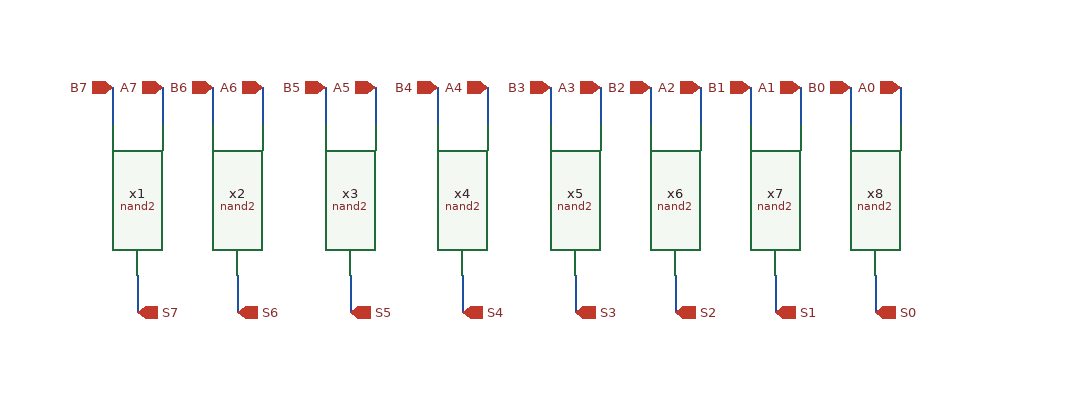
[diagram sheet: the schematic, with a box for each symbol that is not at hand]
v {xschem version=3.1.0 file_version=1.2 }
G {}
K {}
V {}
S {}
E {}
N 2260 -940 2260 -910 {
lab=A7}
N 2430 -940 2430 -910 {
lab=A5}
N 2340 -940 2340 -910 {
lab=A6}
N 2520 -940 2520 -910 {
lab=A4}
N 2610 -940 2610 -910 {
lab=A3}
N 2690 -940 2690 -910 {
lab=A2}
N 2770 -940 2770 -910 {
lab=A1}
N 2850 -940 2850 -910 {
lab=A0}
N 2220 -940 2220 -910 {
lab=B7}
N 2390 -940 2390 -910 {
lab=B5}
N 2300 -940 2300 -910 {
lab=B6}
N 2480 -940 2480 -910 {
lab=B4}
N 2570 -940 2570 -910 {
lab=B3}
N 2650 -940 2650 -910 {
lab=B2}
N 2730 -940 2730 -910 {
lab=B1}
N 2810 -940 2810 -910 {
lab=A0}
N 2240 -790 2240 -760 {
lab=S7}
N 2320 -790 2320 -760 {
lab=S6}
N 2410 -790 2410 -760 {
lab=S5}
N 2500 -790 2500 -760 {
lab=S4}
N 2590 -790 2590 -760 {
lab=S3}
N 2670 -790 2670 -760 {
lab=S2}
N 2750 -790 2750 -760 {
lab=S1}
N 2830 -790 2830 -760 {
lab=S0}
C {NAND/nand2.sym} 2240 -850 1 0 {name=x1 VSS=VSS VDD=VDD}
C {NAND/nand2.sym} 2320 -850 1 0 {name=x2 VSS=VSS VDD=VDD}
C {NAND/nand2.sym} 2410 -850 1 0 {name=x3 VSS=VSS VDD=VDD}
C {NAND/nand2.sym} 2500 -850 1 0 {name=x4 VSS=VSS VDD=VDD}
C {NAND/nand2.sym} 2590 -850 1 0 {name=x5 VSS=VSS VDD=VDD}
C {NAND/nand2.sym} 2670 -850 1 0 {name=x6 VSS=VSS VDD=VDD}
C {NAND/nand2.sym} 2750 -850 1 0 {name=x7 VSS=VSS VDD=VDD}
C {NAND/nand2.sym} 2830 -850 1 0 {name=x8 VSS=VSS VDD=VDD}
C {devices/ipin.sym} 2260 -940 1 0 {name=p1 lab=A7}
C {devices/ipin.sym} 2430 -940 1 0 {name=p2 lab=A5}
C {devices/ipin.sym} 2340 -940 1 0 {name=p3 lab=A6}
C {devices/ipin.sym} 2520 -940 1 0 {name=p4 lab=A4}
C {devices/ipin.sym} 2610 -940 1 0 {name=p5 lab=A3}
C {devices/ipin.sym} 2690 -940 1 0 {name=p6 lab=A2}
C {devices/ipin.sym} 2770 -940 1 0 {name=p7 lab=A1}
C {devices/ipin.sym} 2850 -940 1 0 {name=p8 lab=A0}
C {devices/ipin.sym} 2220 -940 1 0 {name=p9 lab=B7}
C {devices/ipin.sym} 2390 -940 1 0 {name=p10 lab=B5}
C {devices/ipin.sym} 2300 -940 1 0 {name=p11 lab=B6}
C {devices/ipin.sym} 2480 -940 1 0 {name=p12 lab=B4}
C {devices/ipin.sym} 2570 -940 1 0 {name=p13 lab=B3}
C {devices/ipin.sym} 2650 -940 1 0 {name=p14 lab=B2}
C {devices/ipin.sym} 2730 -940 1 0 {name=p15 lab=B1}
C {devices/ipin.sym} 2810 -940 1 0 {name=p16 lab=B0}
C {devices/opin.sym} 2240 -760 1 0 {name=p17 lab=S7}
C {devices/opin.sym} 2320 -760 1 0 {name=p18 lab=S6}
C {devices/opin.sym} 2410 -760 1 0 {name=p19 lab=S5}
C {devices/opin.sym} 2500 -760 1 0 {name=p20 lab=S4}
C {devices/opin.sym} 2590 -760 1 0 {name=p21 lab=S3}
C {devices/opin.sym} 2670 -760 1 0 {name=p22 lab=S2}
C {devices/opin.sym} 2750 -760 1 0 {name=p23 lab=S1}
C {devices/opin.sym} 2830 -760 1 0 {name=p24 lab=S0}
